VERSION 5.7 ;
  NOWIREEXTENSIONATPIN ON ;
  DIVIDERCHAR "/" ;
  BUSBITCHARS "[]" ;
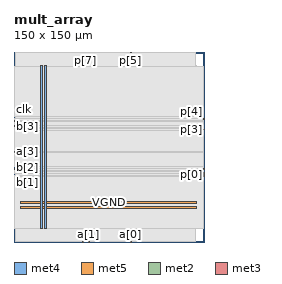
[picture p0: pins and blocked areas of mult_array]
MACRO mult_array
  CLASS BLOCK ;
  FOREIGN mult_array ;
  ORIGIN 0.000 0.000 ;
  SIZE 150.000 BY 150.000 ;
  PIN VGND
    DIRECTION INOUT ;
    USE GROUND ;
    PORT
      LAYER met4 ;
        RECT 24.340 10.640 25.940 138.960 ;
    END
    PORT
      LAYER met5 ;
        RECT 5.520 30.030 144.440 31.630 ;
    END
  END VGND
  PIN VPWR
    DIRECTION INOUT ;
    USE POWER ;
    PORT
      LAYER met4 ;
        RECT 21.040 10.640 22.640 138.960 ;
    END
    PORT
      LAYER met5 ;
        RECT 5.520 26.730 144.440 28.330 ;
    END
  END VPWR
  PIN a[0]
    DIRECTION INPUT ;
    USE SIGNAL ;
    ANTENNAGATEAREA 0.159000 ;
    PORT
      LAYER met2 ;
        RECT 92.090 0.000 92.370 0.280 ;
    END
  END a[0]
  PIN a[1]
    DIRECTION INPUT ;
    USE SIGNAL ;
    ANTENNAGATEAREA 0.159000 ;
    PORT
      LAYER met2 ;
        RECT 58.970 0.000 59.250 0.280 ;
    END
  END a[1]
  PIN a[2]
    DIRECTION INPUT ;
    USE SIGNAL ;
    ANTENNAGATEAREA 0.159000 ;
    PORT
      LAYER met3 ;
        RECT 0.000 57.160 0.600 57.760 ;
    END
  END a[2]
  PIN a[3]
    DIRECTION INPUT ;
    USE SIGNAL ;
    ANTENNAGATEAREA 0.159000 ;
    PORT
      LAYER met3 ;
        RECT 0.000 70.760 0.600 71.360 ;
    END
  END a[3]
  PIN b[0]
    DIRECTION INPUT ;
    USE SIGNAL ;
    ANTENNAGATEAREA 0.159000 ;
    PORT
      LAYER met2 ;
        RECT 54.370 0.000 54.650 0.280 ;
    END
  END b[0]
  PIN b[1]
    DIRECTION INPUT ;
    USE SIGNAL ;
    ANTENNAGATEAREA 0.159000 ;
    PORT
      LAYER met3 ;
        RECT 0.000 53.080 0.600 53.680 ;
    END
  END b[1]
  PIN b[2]
    DIRECTION INPUT ;
    USE SIGNAL ;
    ANTENNAGATEAREA 0.159000 ;
    PORT
      LAYER met3 ;
        RECT 0.000 58.520 0.600 59.120 ;
    END
  END b[2]
  PIN b[3]
    DIRECTION INPUT ;
    USE SIGNAL ;
    ANTENNAGATEAREA 0.159000 ;
    PORT
      LAYER met3 ;
        RECT 0.000 91.160 0.600 91.760 ;
    END
  END b[3]
  PIN clk
    DIRECTION INPUT ;
    USE SIGNAL ;
    ANTENNAGATEAREA 0.852000 ;
    PORT
      LAYER met3 ;
        RECT 0.000 97.960 0.600 98.560 ;
    END
  END clk
  PIN p[0]
    DIRECTION OUTPUT ;
    USE SIGNAL ;
    ANTENNADIFFAREA 0.445500 ;
    PORT
      LAYER met3 ;
        RECT 149.400 53.080 150.000 53.680 ;
    END
  END p[0]
  PIN p[1]
    DIRECTION OUTPUT ;
    USE SIGNAL ;
    ANTENNADIFFAREA 0.445500 ;
    PORT
      LAYER met3 ;
        RECT 149.400 51.720 150.000 52.320 ;
    END
  END p[1]
  PIN p[2]
    DIRECTION OUTPUT ;
    USE SIGNAL ;
    ANTENNADIFFAREA 0.445500 ;
    PORT
      LAYER met3 ;
        RECT 149.400 57.160 150.000 57.760 ;
    END
  END p[2]
  PIN p[3]
    DIRECTION OUTPUT ;
    USE SIGNAL ;
    ANTENNADIFFAREA 0.445500 ;
    PORT
      LAYER met3 ;
        RECT 149.400 88.440 150.000 89.040 ;
    END
  END p[3]
  PIN p[4]
    DIRECTION OUTPUT ;
    USE SIGNAL ;
    ANTENNADIFFAREA 0.445500 ;
    PORT
      LAYER met3 ;
        RECT 149.400 96.600 150.000 97.200 ;
    END
  END p[4]
  PIN p[5]
    DIRECTION OUTPUT ;
    USE SIGNAL ;
    ANTENNADIFFAREA 0.445500 ;
    PORT
      LAYER met2 ;
        RECT 92.090 149.720 92.370 150.000 ;
    END
  END p[5]
  PIN p[6]
    DIRECTION OUTPUT ;
    USE SIGNAL ;
    ANTENNADIFFAREA 0.445500 ;
    PORT
      LAYER met3 ;
        RECT 0.000 95.240 0.600 95.840 ;
    END
  END p[6]
  PIN p[7]
    DIRECTION OUTPUT ;
    USE SIGNAL ;
    ANTENNADIFFAREA 0.445500 ;
    PORT
      LAYER met2 ;
        RECT 56.210 149.720 56.490 150.000 ;
    END
  END p[7]
  PIN rst_n
    DIRECTION INPUT ;
    USE SIGNAL ;
    ANTENNAGATEAREA 0.159000 ;
    PORT
      LAYER met3 ;
        RECT 149.400 54.440 150.000 55.040 ;
    END
  END rst_n
  OBS
      LAYER nwell ;
        RECT 5.330 10.795 144.630 138.910 ;
      LAYER li1 ;
        RECT 5.520 10.795 144.440 138.805 ;
      LAYER met1 ;
        RECT 1.450 10.640 144.440 138.960 ;
      LAYER met2 ;
        RECT 1.470 149.440 55.930 149.720 ;
        RECT 56.770 149.440 91.810 149.720 ;
        RECT 92.650 149.440 142.970 149.720 ;
        RECT 1.470 0.560 142.970 149.440 ;
        RECT 1.470 0.280 54.090 0.560 ;
        RECT 54.930 0.280 58.690 0.560 ;
        RECT 59.530 0.280 91.810 0.560 ;
        RECT 92.650 0.280 142.970 0.560 ;
      LAYER met3 ;
        RECT 0.600 98.960 149.400 138.885 ;
        RECT 1.000 97.600 149.400 98.960 ;
        RECT 1.000 97.560 149.000 97.600 ;
        RECT 0.600 96.240 149.000 97.560 ;
        RECT 1.000 96.200 149.000 96.240 ;
        RECT 1.000 94.840 149.400 96.200 ;
        RECT 0.600 92.160 149.400 94.840 ;
        RECT 1.000 90.760 149.400 92.160 ;
        RECT 0.600 89.440 149.400 90.760 ;
        RECT 0.600 88.040 149.000 89.440 ;
        RECT 0.600 71.760 149.400 88.040 ;
        RECT 1.000 70.360 149.400 71.760 ;
        RECT 0.600 59.520 149.400 70.360 ;
        RECT 1.000 58.160 149.400 59.520 ;
        RECT 1.000 56.760 149.000 58.160 ;
        RECT 0.600 55.440 149.400 56.760 ;
        RECT 0.600 54.080 149.000 55.440 ;
        RECT 1.000 52.680 149.000 54.080 ;
        RECT 0.600 51.320 149.000 52.680 ;
        RECT 0.600 10.715 149.400 51.320 ;
  END
END mult_array
END LIBRARY

